VERSION 5.7 ;
  NOWIREEXTENSIONATPIN ON ;
  DIVIDERCHAR "/" ;
  BUSBITCHARS "[]" ;
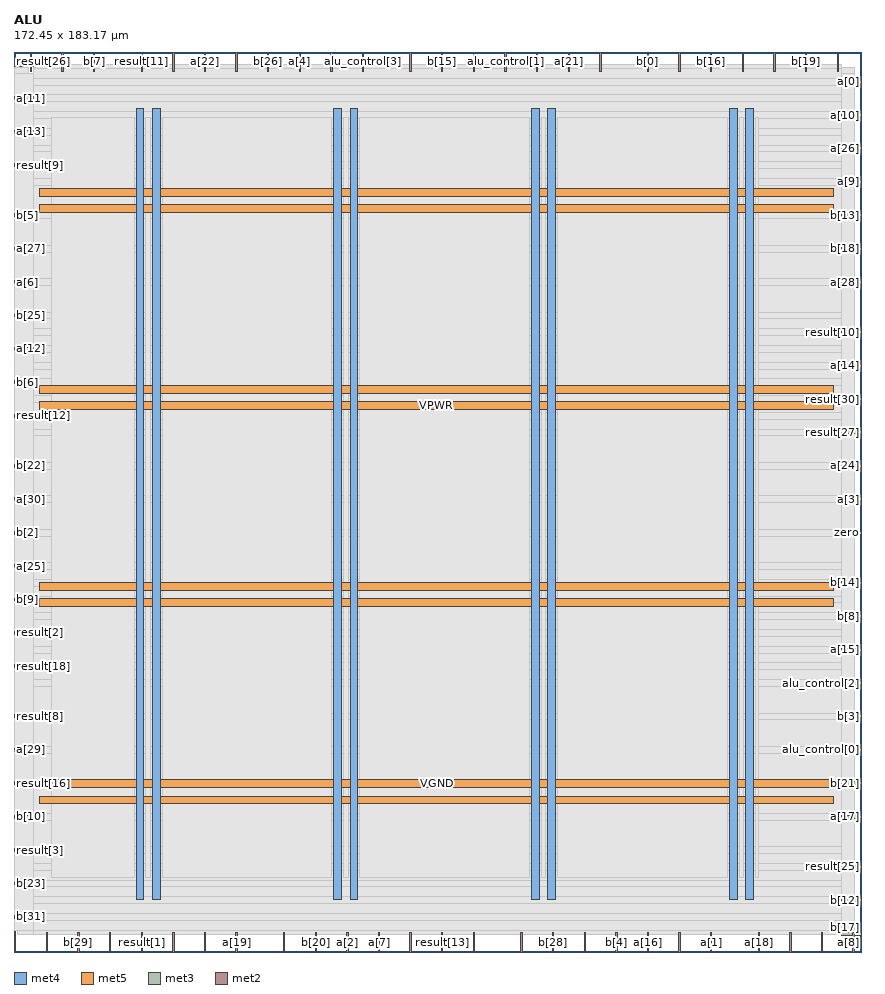
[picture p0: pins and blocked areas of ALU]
MACRO ALU
  CLASS BLOCK ;
  FOREIGN ALU ;
  ORIGIN 0.000 0.000 ;
  SIZE 172.450 BY 183.170 ;
  PIN VGND
    DIRECTION INOUT ;
    USE GROUND ;
    PORT
      LAYER met4 ;
        RECT 28.145 10.640 29.745 171.600 ;
    END
    PORT
      LAYER met4 ;
        RECT 68.395 10.640 69.995 171.600 ;
    END
    PORT
      LAYER met4 ;
        RECT 108.645 10.640 110.245 171.600 ;
    END
    PORT
      LAYER met4 ;
        RECT 148.895 10.640 150.495 171.600 ;
    END
    PORT
      LAYER met5 ;
        RECT 5.280 33.440 166.760 35.040 ;
    END
    PORT
      LAYER met5 ;
        RECT 5.280 73.560 166.760 75.160 ;
    END
    PORT
      LAYER met5 ;
        RECT 5.280 113.680 166.760 115.280 ;
    END
    PORT
      LAYER met5 ;
        RECT 5.280 153.800 166.760 155.400 ;
    END
  END VGND
  PIN VPWR
    DIRECTION INOUT ;
    USE POWER ;
    PORT
      LAYER met4 ;
        RECT 24.845 10.640 26.445 171.600 ;
    END
    PORT
      LAYER met4 ;
        RECT 65.095 10.640 66.695 171.600 ;
    END
    PORT
      LAYER met4 ;
        RECT 105.345 10.640 106.945 171.600 ;
    END
    PORT
      LAYER met4 ;
        RECT 145.595 10.640 147.195 171.600 ;
    END
    PORT
      LAYER met5 ;
        RECT 5.280 30.140 166.760 31.740 ;
    END
    PORT
      LAYER met5 ;
        RECT 5.280 70.260 166.760 71.860 ;
    END
    PORT
      LAYER met5 ;
        RECT 5.280 110.380 166.760 111.980 ;
    END
    PORT
      LAYER met5 ;
        RECT 5.280 150.500 166.760 152.100 ;
    END
  END VPWR
  PIN a[0]
    DIRECTION INPUT ;
    USE SIGNAL ;
    ANTENNAGATEAREA 0.213000 ;
    PORT
      LAYER met3 ;
        RECT 168.450 176.840 172.450 177.440 ;
    END
  END a[0]
  PIN a[10]
    DIRECTION INPUT ;
    USE SIGNAL ;
    ANTENNAGATEAREA 0.213000 ;
    PORT
      LAYER met3 ;
        RECT 168.450 170.040 172.450 170.640 ;
    END
  END a[10]
  PIN a[11]
    DIRECTION INPUT ;
    USE SIGNAL ;
    ANTENNAGATEAREA 0.159000 ;
    PORT
      LAYER met3 ;
        RECT 0.000 173.440 4.000 174.040 ;
    END
  END a[11]
  PIN a[12]
    DIRECTION INPUT ;
    USE SIGNAL ;
    ANTENNAGATEAREA 0.196500 ;
    PORT
      LAYER met3 ;
        RECT 0.000 122.440 4.000 123.040 ;
    END
  END a[12]
  PIN a[13]
    DIRECTION INPUT ;
    USE SIGNAL ;
    ANTENNAGATEAREA 0.213000 ;
    PORT
      LAYER met3 ;
        RECT 0.000 166.640 4.000 167.240 ;
    END
  END a[13]
  PIN a[14]
    DIRECTION INPUT ;
    USE SIGNAL ;
    ANTENNAGATEAREA 0.196500 ;
    PORT
      LAYER met3 ;
        RECT 168.450 119.040 172.450 119.640 ;
    END
  END a[14]
  PIN a[15]
    DIRECTION INPUT ;
    USE SIGNAL ;
    ANTENNAGATEAREA 0.213000 ;
    PORT
      LAYER met3 ;
        RECT 168.450 61.240 172.450 61.840 ;
    END
  END a[15]
  PIN a[16]
    DIRECTION INPUT ;
    USE SIGNAL ;
    ANTENNAGATEAREA 0.213000 ;
    PORT
      LAYER met2 ;
        RECT 128.890 0.000 129.170 4.000 ;
    END
  END a[16]
  PIN a[17]
    DIRECTION INPUT ;
    USE SIGNAL ;
    ANTENNAGATEAREA 0.196500 ;
    PORT
      LAYER met3 ;
        RECT 168.450 27.240 172.450 27.840 ;
    END
  END a[17]
  PIN a[18]
    DIRECTION INPUT ;
    USE SIGNAL ;
    ANTENNAGATEAREA 0.196500 ;
    PORT
      LAYER met2 ;
        RECT 151.430 0.000 151.710 4.000 ;
    END
  END a[18]
  PIN a[19]
    DIRECTION INPUT ;
    USE SIGNAL ;
    ANTENNAGATEAREA 0.213000 ;
    PORT
      LAYER met2 ;
        RECT 45.170 0.000 45.450 4.000 ;
    END
  END a[19]
  PIN a[1]
    DIRECTION INPUT ;
    USE SIGNAL ;
    ANTENNAGATEAREA 0.213000 ;
    PORT
      LAYER met2 ;
        RECT 141.770 0.000 142.050 4.000 ;
    END
  END a[1]
  PIN a[20]
    DIRECTION INPUT ;
    USE SIGNAL ;
    ANTENNAGATEAREA 0.213000 ;
    PORT
      LAYER met2 ;
        RECT 19.410 0.000 19.690 4.000 ;
    END
  END a[20]
  PIN a[21]
    DIRECTION INPUT ;
    USE SIGNAL ;
    ANTENNAGATEAREA 0.196500 ;
    PORT
      LAYER met2 ;
        RECT 112.790 179.170 113.070 183.170 ;
    END
  END a[21]
  PIN a[22]
    DIRECTION INPUT ;
    USE SIGNAL ;
    ANTENNAGATEAREA 0.213000 ;
    PORT
      LAYER met2 ;
        RECT 38.730 179.170 39.010 183.170 ;
    END
  END a[22]
  PIN a[23]
    DIRECTION INPUT ;
    USE SIGNAL ;
    ANTENNAGATEAREA 0.213000 ;
    PORT
      LAYER met2 ;
        RECT 45.170 179.170 45.450 183.170 ;
    END
  END a[23]
  PIN a[24]
    DIRECTION INPUT ;
    USE SIGNAL ;
    ANTENNAGATEAREA 0.159000 ;
    PORT
      LAYER met3 ;
        RECT 168.450 98.640 172.450 99.240 ;
    END
  END a[24]
  PIN a[25]
    DIRECTION INPUT ;
    USE SIGNAL ;
    ANTENNAGATEAREA 0.213000 ;
    PORT
      LAYER met3 ;
        RECT 0.000 78.240 4.000 78.840 ;
    END
  END a[25]
  PIN a[26]
    DIRECTION INPUT ;
    USE SIGNAL ;
    ANTENNAGATEAREA 0.159000 ;
    PORT
      LAYER met3 ;
        RECT 168.450 163.240 172.450 163.840 ;
    END
  END a[26]
  PIN a[27]
    DIRECTION INPUT ;
    USE SIGNAL ;
    ANTENNAGATEAREA 0.213000 ;
    PORT
      LAYER met3 ;
        RECT 0.000 142.840 4.000 143.440 ;
    END
  END a[27]
  PIN a[28]
    DIRECTION INPUT ;
    USE SIGNAL ;
    ANTENNAGATEAREA 0.159000 ;
    PORT
      LAYER met3 ;
        RECT 168.450 136.040 172.450 136.640 ;
    END
  END a[28]
  PIN a[29]
    DIRECTION INPUT ;
    USE SIGNAL ;
    ANTENNAGATEAREA 0.213000 ;
    PORT
      LAYER met3 ;
        RECT 0.000 40.840 4.000 41.440 ;
    END
  END a[29]
  PIN a[2]
    DIRECTION INPUT ;
    USE SIGNAL ;
    ANTENNAGATEAREA 0.213000 ;
    PORT
      LAYER met2 ;
        RECT 67.710 0.000 67.990 4.000 ;
    END
  END a[2]
  PIN a[30]
    DIRECTION INPUT ;
    USE SIGNAL ;
    ANTENNAGATEAREA 0.213000 ;
    PORT
      LAYER met3 ;
        RECT 0.000 91.840 4.000 92.440 ;
    END
  END a[30]
  PIN a[31]
    DIRECTION INPUT ;
    USE SIGNAL ;
    ANTENNAGATEAREA 0.213000 ;
    PORT
      LAYER met2 ;
        RECT 106.350 179.170 106.630 183.170 ;
    END
  END a[31]
  PIN a[3]
    DIRECTION INPUT ;
    USE SIGNAL ;
    ANTENNAGATEAREA 0.126000 ;
    PORT
      LAYER met3 ;
        RECT 168.450 91.840 172.450 92.440 ;
    END
  END a[3]
  PIN a[4]
    DIRECTION INPUT ;
    USE SIGNAL ;
    ANTENNAGATEAREA 0.213000 ;
    PORT
      LAYER met2 ;
        RECT 58.050 179.170 58.330 183.170 ;
    END
  END a[4]
  PIN a[5]
    DIRECTION INPUT ;
    USE SIGNAL ;
    ANTENNAGATEAREA 0.213000 ;
    PORT
      LAYER met2 ;
        RECT 64.490 179.170 64.770 183.170 ;
    END
  END a[5]
  PIN a[6]
    DIRECTION INPUT ;
    USE SIGNAL ;
    ANTENNAGATEAREA 0.213000 ;
    PORT
      LAYER met3 ;
        RECT 0.000 136.040 4.000 136.640 ;
    END
  END a[6]
  PIN a[7]
    DIRECTION INPUT ;
    USE SIGNAL ;
    ANTENNAGATEAREA 0.126000 ;
    PORT
      LAYER met2 ;
        RECT 74.150 0.000 74.430 4.000 ;
    END
  END a[7]
  PIN a[8]
    DIRECTION INPUT ;
    USE SIGNAL ;
    ANTENNAGATEAREA 0.213000 ;
    PORT
      LAYER met2 ;
        RECT 170.750 0.000 171.030 4.000 ;
    END
  END a[8]
  PIN a[9]
    DIRECTION INPUT ;
    USE SIGNAL ;
    ANTENNAGATEAREA 0.159000 ;
    PORT
      LAYER met3 ;
        RECT 168.450 156.440 172.450 157.040 ;
    END
  END a[9]
  PIN alu_control[0]
    DIRECTION INPUT ;
    USE SIGNAL ;
    ANTENNAGATEAREA 0.159000 ;
    PORT
      LAYER met3 ;
        RECT 168.450 40.840 172.450 41.440 ;
    END
  END alu_control[0]
  PIN alu_control[1]
    DIRECTION INPUT ;
    USE SIGNAL ;
    ANTENNAGATEAREA 0.159000 ;
    PORT
      LAYER met2 ;
        RECT 99.910 179.170 100.190 183.170 ;
    END
  END alu_control[1]
  PIN alu_control[2]
    DIRECTION INPUT ;
    USE SIGNAL ;
    ANTENNAGATEAREA 0.213000 ;
    PORT
      LAYER met3 ;
        RECT 168.450 54.440 172.450 55.040 ;
    END
  END alu_control[2]
  PIN alu_control[3]
    DIRECTION INPUT ;
    USE SIGNAL ;
    ANTENNAGATEAREA 0.159000 ;
    PORT
      LAYER met2 ;
        RECT 70.930 179.170 71.210 183.170 ;
    END
  END alu_control[3]
  PIN b[0]
    DIRECTION INPUT ;
    USE SIGNAL ;
    ANTENNAGATEAREA 0.213000 ;
    PORT
      LAYER met2 ;
        RECT 128.890 179.170 129.170 183.170 ;
    END
  END b[0]
  PIN b[10]
    DIRECTION INPUT ;
    USE SIGNAL ;
    ANTENNAGATEAREA 0.213000 ;
    PORT
      LAYER met3 ;
        RECT 0.000 27.240 4.000 27.840 ;
    END
  END b[10]
  PIN b[11]
    DIRECTION INPUT ;
    USE SIGNAL ;
    ANTENNAGATEAREA 0.213000 ;
    PORT
      LAYER met2 ;
        RECT 38.730 0.000 39.010 4.000 ;
    END
  END b[11]
  PIN b[12]
    DIRECTION INPUT ;
    USE SIGNAL ;
    ANTENNAGATEAREA 0.159000 ;
    PORT
      LAYER met3 ;
        RECT 168.450 10.240 172.450 10.840 ;
    END
  END b[12]
  PIN b[13]
    DIRECTION INPUT ;
    USE SIGNAL ;
    ANTENNAGATEAREA 0.159000 ;
    PORT
      LAYER met3 ;
        RECT 168.450 149.640 172.450 150.240 ;
    END
  END b[13]
  PIN b[14]
    DIRECTION INPUT ;
    USE SIGNAL ;
    ANTENNAGATEAREA 0.213000 ;
    PORT
      LAYER met3 ;
        RECT 168.450 74.840 172.450 75.440 ;
    END
  END b[14]
  PIN b[15]
    DIRECTION INPUT ;
    USE SIGNAL ;
    ANTENNAGATEAREA 0.159000 ;
    PORT
      LAYER met2 ;
        RECT 87.030 179.170 87.310 183.170 ;
    END
  END b[15]
  PIN b[16]
    DIRECTION INPUT ;
    USE SIGNAL ;
    ANTENNAGATEAREA 0.213000 ;
    PORT
      LAYER met2 ;
        RECT 141.770 179.170 142.050 183.170 ;
    END
  END b[16]
  PIN b[17]
    DIRECTION INPUT ;
    USE SIGNAL ;
    ANTENNAGATEAREA 0.213000 ;
    PORT
      LAYER met3 ;
        RECT 168.450 3.440 172.450 4.040 ;
    END
  END b[17]
  PIN b[18]
    DIRECTION INPUT ;
    USE SIGNAL ;
    ANTENNAGATEAREA 0.159000 ;
    PORT
      LAYER met3 ;
        RECT 168.450 142.840 172.450 143.440 ;
    END
  END b[18]
  PIN b[19]
    DIRECTION INPUT ;
    USE SIGNAL ;
    ANTENNAGATEAREA 0.159000 ;
    PORT
      LAYER met2 ;
        RECT 161.090 179.170 161.370 183.170 ;
    END
  END b[19]
  PIN b[1]
    DIRECTION INPUT ;
    USE SIGNAL ;
    ANTENNAGATEAREA 0.196500 ;
    PORT
      LAYER met2 ;
        RECT 93.470 179.170 93.750 183.170 ;
    END
  END b[1]
  PIN b[20]
    DIRECTION INPUT ;
    USE SIGNAL ;
    ANTENNAGATEAREA 0.159000 ;
    PORT
      LAYER met2 ;
        RECT 61.270 0.000 61.550 4.000 ;
    END
  END b[20]
  PIN b[21]
    DIRECTION INPUT ;
    USE SIGNAL ;
    ANTENNAGATEAREA 0.126000 ;
    PORT
      LAYER met3 ;
        RECT 168.450 34.040 172.450 34.640 ;
    END
  END b[21]
  PIN b[22]
    DIRECTION INPUT ;
    USE SIGNAL ;
    ANTENNAGATEAREA 0.159000 ;
    PORT
      LAYER met3 ;
        RECT 0.000 98.640 4.000 99.240 ;
    END
  END b[22]
  PIN b[23]
    DIRECTION INPUT ;
    USE SIGNAL ;
    ANTENNAGATEAREA 0.159000 ;
    PORT
      LAYER met3 ;
        RECT 0.000 13.640 4.000 14.240 ;
    END
  END b[23]
  PIN b[24]
    DIRECTION INPUT ;
    USE SIGNAL ;
    ANTENNAGATEAREA 0.159000 ;
    PORT
      LAYER met2 ;
        RECT 164.310 0.000 164.590 4.000 ;
    END
  END b[24]
  PIN b[25]
    DIRECTION INPUT ;
    USE SIGNAL ;
    ANTENNAGATEAREA 0.159000 ;
    PORT
      LAYER met3 ;
        RECT 0.000 129.240 4.000 129.840 ;
    END
  END b[25]
  PIN b[26]
    DIRECTION INPUT ;
    USE SIGNAL ;
    ANTENNAGATEAREA 0.213000 ;
    PORT
      LAYER met2 ;
        RECT 51.610 179.170 51.890 183.170 ;
    END
  END b[26]
  PIN b[27]
    DIRECTION INPUT ;
    USE SIGNAL ;
    ANTENNAGATEAREA 0.213000 ;
    PORT
      LAYER met2 ;
        RECT 148.210 179.170 148.490 183.170 ;
    END
  END b[27]
  PIN b[28]
    DIRECTION INPUT ;
    USE SIGNAL ;
    ANTENNAGATEAREA 0.159000 ;
    PORT
      LAYER met2 ;
        RECT 109.570 0.000 109.850 4.000 ;
    END
  END b[28]
  PIN b[29]
    DIRECTION INPUT ;
    USE SIGNAL ;
    ANTENNAGATEAREA 0.159000 ;
    PORT
      LAYER met2 ;
        RECT 12.970 0.000 13.250 4.000 ;
    END
  END b[29]
  PIN b[2]
    DIRECTION INPUT ;
    USE SIGNAL ;
    ANTENNAGATEAREA 0.196500 ;
    PORT
      LAYER met3 ;
        RECT 0.000 85.040 4.000 85.640 ;
    END
  END b[2]
  PIN b[30]
    DIRECTION INPUT ;
    USE SIGNAL ;
    ANTENNAGATEAREA 0.213000 ;
    PORT
      LAYER met2 ;
        RECT 157.870 0.000 158.150 4.000 ;
    END
  END b[30]
  PIN b[31]
    DIRECTION INPUT ;
    USE SIGNAL ;
    ANTENNAGATEAREA 0.213000 ;
    PORT
      LAYER met3 ;
        RECT 0.000 6.840 4.000 7.440 ;
    END
  END b[31]
  PIN b[3]
    DIRECTION INPUT ;
    USE SIGNAL ;
    ANTENNAGATEAREA 0.159000 ;
    PORT
      LAYER met3 ;
        RECT 168.450 47.640 172.450 48.240 ;
    END
  END b[3]
  PIN b[4]
    DIRECTION INPUT ;
    USE SIGNAL ;
    ANTENNAGATEAREA 0.213000 ;
    PORT
      LAYER met2 ;
        RECT 122.450 0.000 122.730 4.000 ;
    END
  END b[4]
  PIN b[5]
    DIRECTION INPUT ;
    USE SIGNAL ;
    ANTENNAGATEAREA 0.213000 ;
    PORT
      LAYER met3 ;
        RECT 0.000 149.640 4.000 150.240 ;
    END
  END b[5]
  PIN b[6]
    DIRECTION INPUT ;
    USE SIGNAL ;
    ANTENNAGATEAREA 0.213000 ;
    PORT
      LAYER met3 ;
        RECT 0.000 115.640 4.000 116.240 ;
    END
  END b[6]
  PIN b[7]
    DIRECTION INPUT ;
    USE SIGNAL ;
    ANTENNAGATEAREA 0.213000 ;
    PORT
      LAYER met2 ;
        RECT 16.190 179.170 16.470 183.170 ;
    END
  END b[7]
  PIN b[8]
    DIRECTION INPUT ;
    USE SIGNAL ;
    ANTENNAGATEAREA 0.159000 ;
    PORT
      LAYER met3 ;
        RECT 168.450 68.040 172.450 68.640 ;
    END
  END b[8]
  PIN b[9]
    DIRECTION INPUT ;
    USE SIGNAL ;
    ANTENNAGATEAREA 0.213000 ;
    PORT
      LAYER met3 ;
        RECT 0.000 71.440 4.000 72.040 ;
    END
  END b[9]
  PIN result[0]
    DIRECTION OUTPUT TRISTATE ;
    USE SIGNAL ;
    ANTENNADIFFAREA 0.795200 ;
    PORT
      LAYER met2 ;
        RECT 135.330 0.000 135.610 4.000 ;
    END
  END result[0]
  PIN result[10]
    DIRECTION OUTPUT TRISTATE ;
    USE SIGNAL ;
    ANTENNADIFFAREA 0.795200 ;
    PORT
      LAYER met3 ;
        RECT 168.450 125.840 172.450 126.440 ;
    END
  END result[10]
  PIN result[11]
    DIRECTION OUTPUT TRISTATE ;
    USE SIGNAL ;
    ANTENNADIFFAREA 0.795200 ;
    PORT
      LAYER met2 ;
        RECT 25.850 179.170 26.130 183.170 ;
    END
  END result[11]
  PIN result[12]
    DIRECTION OUTPUT TRISTATE ;
    USE SIGNAL ;
    ANTENNADIFFAREA 0.795200 ;
    PORT
      LAYER met3 ;
        RECT 0.000 108.840 4.000 109.440 ;
    END
  END result[12]
  PIN result[13]
    DIRECTION OUTPUT TRISTATE ;
    USE SIGNAL ;
    ANTENNADIFFAREA 0.795200 ;
    PORT
      LAYER met2 ;
        RECT 87.030 0.000 87.310 4.000 ;
    END
  END result[13]
  PIN result[14]
    DIRECTION OUTPUT TRISTATE ;
    USE SIGNAL ;
    ANTENNADIFFAREA 0.795200 ;
    PORT
      LAYER met2 ;
        RECT 0.090 0.000 0.370 4.000 ;
    END
  END result[14]
  PIN result[15]
    DIRECTION OUTPUT TRISTATE ;
    USE SIGNAL ;
    ANTENNADIFFAREA 0.795200 ;
    PORT
      LAYER met2 ;
        RECT 103.130 0.000 103.410 4.000 ;
    END
  END result[15]
  PIN result[16]
    DIRECTION OUTPUT TRISTATE ;
    USE SIGNAL ;
    ANTENNADIFFAREA 0.795200 ;
    PORT
      LAYER met3 ;
        RECT 0.000 34.040 4.000 34.640 ;
    END
  END result[16]
  PIN result[17]
    DIRECTION OUTPUT TRISTATE ;
    USE SIGNAL ;
    ANTENNADIFFAREA 0.795200 ;
    PORT
      LAYER met2 ;
        RECT 80.590 179.170 80.870 183.170 ;
    END
  END result[17]
  PIN result[18]
    DIRECTION OUTPUT TRISTATE ;
    USE SIGNAL ;
    ANTENNADIFFAREA 0.795200 ;
    PORT
      LAYER met3 ;
        RECT 0.000 57.840 4.000 58.440 ;
    END
  END result[18]
  PIN result[19]
    DIRECTION OUTPUT TRISTATE ;
    USE SIGNAL ;
    ANTENNADIFFAREA 0.795200 ;
    PORT
      LAYER met3 ;
        RECT 0.000 180.240 4.000 180.840 ;
    END
  END result[19]
  PIN result[1]
    DIRECTION OUTPUT TRISTATE ;
    USE SIGNAL ;
    ANTENNADIFFAREA 0.795200 ;
    PORT
      LAYER met2 ;
        RECT 25.850 0.000 26.130 4.000 ;
    END
  END result[1]
  PIN result[20]
    DIRECTION OUTPUT TRISTATE ;
    USE SIGNAL ;
    ANTENNADIFFAREA 0.795200 ;
    PORT
      LAYER met2 ;
        RECT 6.530 0.000 6.810 4.000 ;
    END
  END result[20]
  PIN result[21]
    DIRECTION OUTPUT TRISTATE ;
    USE SIGNAL ;
    ANTENNADIFFAREA 0.795200 ;
    PORT
      LAYER met2 ;
        RECT 154.650 179.170 154.930 183.170 ;
    END
  END result[21]
  PIN result[22]
    DIRECTION OUTPUT TRISTATE ;
    USE SIGNAL ;
    ANTENNADIFFAREA 0.795200 ;
    PORT
      LAYER met2 ;
        RECT 119.230 179.170 119.510 183.170 ;
    END
  END result[22]
  PIN result[23]
    DIRECTION OUTPUT TRISTATE ;
    USE SIGNAL ;
    ANTENNADIFFAREA 0.795200 ;
    PORT
      LAYER met2 ;
        RECT 80.590 0.000 80.870 4.000 ;
    END
  END result[23]
  PIN result[24]
    DIRECTION OUTPUT TRISTATE ;
    USE SIGNAL ;
    ANTENNADIFFAREA 0.795200 ;
    PORT
      LAYER met2 ;
        RECT 167.530 179.170 167.810 183.170 ;
    END
  END result[24]
  PIN result[25]
    DIRECTION OUTPUT TRISTATE ;
    USE SIGNAL ;
    ANTENNADIFFAREA 0.445500 ;
    PORT
      LAYER met3 ;
        RECT 168.450 17.040 172.450 17.640 ;
    END
  END result[25]
  PIN result[26]
    DIRECTION OUTPUT TRISTATE ;
    USE SIGNAL ;
    ANTENNADIFFAREA 0.795200 ;
    PORT
      LAYER met2 ;
        RECT 3.310 179.170 3.590 183.170 ;
    END
  END result[26]
  PIN result[27]
    DIRECTION OUTPUT TRISTATE ;
    USE SIGNAL ;
    ANTENNADIFFAREA 0.445500 ;
    PORT
      LAYER met3 ;
        RECT 168.450 105.440 172.450 106.040 ;
    END
  END result[27]
  PIN result[28]
    DIRECTION OUTPUT TRISTATE ;
    USE SIGNAL ;
    ANTENNADIFFAREA 0.795200 ;
    PORT
      LAYER met2 ;
        RECT 32.290 0.000 32.570 4.000 ;
    END
  END result[28]
  PIN result[29]
    DIRECTION OUTPUT TRISTATE ;
    USE SIGNAL ;
    ANTENNADIFFAREA 0.795200 ;
    PORT
      LAYER met2 ;
        RECT 54.830 0.000 55.110 4.000 ;
    END
  END result[29]
  PIN result[2]
    DIRECTION OUTPUT TRISTATE ;
    USE SIGNAL ;
    ANTENNADIFFAREA 0.795200 ;
    PORT
      LAYER met3 ;
        RECT 0.000 64.640 4.000 65.240 ;
    END
  END result[2]
  PIN result[30]
    DIRECTION OUTPUT TRISTATE ;
    USE SIGNAL ;
    ANTENNADIFFAREA 0.795200 ;
    PORT
      LAYER met3 ;
        RECT 168.450 112.240 172.450 112.840 ;
    END
  END result[30]
  PIN result[31]
    DIRECTION OUTPUT TRISTATE ;
    USE SIGNAL ;
    ANTENNADIFFAREA 0.795200 ;
    PORT
      LAYER met2 ;
        RECT 93.470 0.000 93.750 4.000 ;
    END
  END result[31]
  PIN result[3]
    DIRECTION OUTPUT TRISTATE ;
    USE SIGNAL ;
    ANTENNADIFFAREA 0.795200 ;
    PORT
      LAYER met3 ;
        RECT 0.000 20.440 4.000 21.040 ;
    END
  END result[3]
  PIN result[4]
    DIRECTION OUTPUT TRISTATE ;
    USE SIGNAL ;
    ANTENNADIFFAREA 0.795200 ;
    PORT
      LAYER met2 ;
        RECT 135.330 179.170 135.610 183.170 ;
    END
  END result[4]
  PIN result[5]
    DIRECTION OUTPUT TRISTATE ;
    USE SIGNAL ;
    ANTENNADIFFAREA 0.445500 ;
    PORT
      LAYER met2 ;
        RECT 9.750 179.170 10.030 183.170 ;
    END
  END result[5]
  PIN result[6]
    DIRECTION OUTPUT TRISTATE ;
    USE SIGNAL ;
    ANTENNADIFFAREA 0.795200 ;
    PORT
      LAYER met2 ;
        RECT 32.290 179.170 32.570 183.170 ;
    END
  END result[6]
  PIN result[7]
    DIRECTION OUTPUT TRISTATE ;
    USE SIGNAL ;
    ANTENNADIFFAREA 0.795200 ;
    PORT
      LAYER met2 ;
        RECT 116.010 0.000 116.290 4.000 ;
    END
  END result[7]
  PIN result[8]
    DIRECTION OUTPUT TRISTATE ;
    USE SIGNAL ;
    ANTENNADIFFAREA 0.795200 ;
    PORT
      LAYER met3 ;
        RECT 0.000 47.640 4.000 48.240 ;
    END
  END result[8]
  PIN result[9]
    DIRECTION OUTPUT TRISTATE ;
    USE SIGNAL ;
    ANTENNADIFFAREA 0.795200 ;
    PORT
      LAYER met3 ;
        RECT 0.000 159.840 4.000 160.440 ;
    END
  END result[9]
  PIN zero
    DIRECTION OUTPUT TRISTATE ;
    USE SIGNAL ;
    ANTENNADIFFAREA 0.445500 ;
    PORT
      LAYER met3 ;
        RECT 168.450 85.040 172.450 85.640 ;
    END
  END zero
  OBS
      LAYER li1 ;
        RECT 5.520 10.795 166.520 171.445 ;
      LAYER met1 ;
        RECT 0.070 8.200 171.050 172.340 ;
      LAYER met2 ;
        RECT 0.100 178.890 3.030 180.045 ;
        RECT 3.870 178.890 9.470 180.045 ;
        RECT 10.310 178.890 15.910 180.045 ;
        RECT 16.750 178.890 25.570 180.045 ;
        RECT 26.410 178.890 32.010 180.045 ;
        RECT 32.850 178.890 38.450 180.045 ;
        RECT 39.290 178.890 44.890 180.045 ;
        RECT 45.730 178.890 51.330 180.045 ;
        RECT 52.170 178.890 57.770 180.045 ;
        RECT 58.610 178.890 64.210 180.045 ;
        RECT 65.050 178.890 70.650 180.045 ;
        RECT 71.490 178.890 80.310 180.045 ;
        RECT 81.150 178.890 86.750 180.045 ;
        RECT 87.590 178.890 93.190 180.045 ;
        RECT 94.030 178.890 99.630 180.045 ;
        RECT 100.470 178.890 106.070 180.045 ;
        RECT 106.910 178.890 112.510 180.045 ;
        RECT 113.350 178.890 118.950 180.045 ;
        RECT 119.790 178.890 128.610 180.045 ;
        RECT 129.450 178.890 135.050 180.045 ;
        RECT 135.890 178.890 141.490 180.045 ;
        RECT 142.330 178.890 147.930 180.045 ;
        RECT 148.770 178.890 154.370 180.045 ;
        RECT 155.210 178.890 160.810 180.045 ;
        RECT 161.650 178.890 167.250 180.045 ;
        RECT 168.090 178.890 171.020 180.045 ;
        RECT 0.100 4.280 171.020 178.890 ;
        RECT 0.650 3.555 6.250 4.280 ;
        RECT 7.090 3.555 12.690 4.280 ;
        RECT 13.530 3.555 19.130 4.280 ;
        RECT 19.970 3.555 25.570 4.280 ;
        RECT 26.410 3.555 32.010 4.280 ;
        RECT 32.850 3.555 38.450 4.280 ;
        RECT 39.290 3.555 44.890 4.280 ;
        RECT 45.730 3.555 54.550 4.280 ;
        RECT 55.390 3.555 60.990 4.280 ;
        RECT 61.830 3.555 67.430 4.280 ;
        RECT 68.270 3.555 73.870 4.280 ;
        RECT 74.710 3.555 80.310 4.280 ;
        RECT 81.150 3.555 86.750 4.280 ;
        RECT 87.590 3.555 93.190 4.280 ;
        RECT 94.030 3.555 102.850 4.280 ;
        RECT 103.690 3.555 109.290 4.280 ;
        RECT 110.130 3.555 115.730 4.280 ;
        RECT 116.570 3.555 122.170 4.280 ;
        RECT 123.010 3.555 128.610 4.280 ;
        RECT 129.450 3.555 135.050 4.280 ;
        RECT 135.890 3.555 141.490 4.280 ;
        RECT 142.330 3.555 151.150 4.280 ;
        RECT 151.990 3.555 157.590 4.280 ;
        RECT 158.430 3.555 164.030 4.280 ;
        RECT 164.870 3.555 170.470 4.280 ;
      LAYER met3 ;
        RECT 4.400 179.840 168.450 180.690 ;
        RECT 3.990 177.840 168.450 179.840 ;
        RECT 3.990 176.440 168.050 177.840 ;
        RECT 3.990 174.440 168.450 176.440 ;
        RECT 4.400 173.040 168.450 174.440 ;
        RECT 3.990 171.040 168.450 173.040 ;
        RECT 3.990 169.640 168.050 171.040 ;
        RECT 3.990 167.640 168.450 169.640 ;
        RECT 4.400 166.240 168.450 167.640 ;
        RECT 3.990 164.240 168.450 166.240 ;
        RECT 3.990 162.840 168.050 164.240 ;
        RECT 3.990 160.840 168.450 162.840 ;
        RECT 4.400 159.440 168.450 160.840 ;
        RECT 3.990 157.440 168.450 159.440 ;
        RECT 3.990 156.040 168.050 157.440 ;
        RECT 3.990 150.640 168.450 156.040 ;
        RECT 4.400 149.240 168.050 150.640 ;
        RECT 3.990 143.840 168.450 149.240 ;
        RECT 4.400 142.440 168.050 143.840 ;
        RECT 3.990 137.040 168.450 142.440 ;
        RECT 4.400 135.640 168.050 137.040 ;
        RECT 3.990 130.240 168.450 135.640 ;
        RECT 4.400 128.840 168.450 130.240 ;
        RECT 3.990 126.840 168.450 128.840 ;
        RECT 3.990 125.440 168.050 126.840 ;
        RECT 3.990 123.440 168.450 125.440 ;
        RECT 4.400 122.040 168.450 123.440 ;
        RECT 3.990 120.040 168.450 122.040 ;
        RECT 3.990 118.640 168.050 120.040 ;
        RECT 3.990 116.640 168.450 118.640 ;
        RECT 4.400 115.240 168.450 116.640 ;
        RECT 3.990 113.240 168.450 115.240 ;
        RECT 3.990 111.840 168.050 113.240 ;
        RECT 3.990 109.840 168.450 111.840 ;
        RECT 4.400 108.440 168.450 109.840 ;
        RECT 3.990 106.440 168.450 108.440 ;
        RECT 3.990 105.040 168.050 106.440 ;
        RECT 3.990 99.640 168.450 105.040 ;
        RECT 4.400 98.240 168.050 99.640 ;
        RECT 3.990 92.840 168.450 98.240 ;
        RECT 4.400 91.440 168.050 92.840 ;
        RECT 3.990 86.040 168.450 91.440 ;
        RECT 4.400 84.640 168.050 86.040 ;
        RECT 3.990 79.240 168.450 84.640 ;
        RECT 4.400 77.840 168.450 79.240 ;
        RECT 3.990 75.840 168.450 77.840 ;
        RECT 3.990 74.440 168.050 75.840 ;
        RECT 3.990 72.440 168.450 74.440 ;
        RECT 4.400 71.040 168.450 72.440 ;
        RECT 3.990 69.040 168.450 71.040 ;
        RECT 3.990 67.640 168.050 69.040 ;
        RECT 3.990 65.640 168.450 67.640 ;
        RECT 4.400 64.240 168.450 65.640 ;
        RECT 3.990 62.240 168.450 64.240 ;
        RECT 3.990 60.840 168.050 62.240 ;
        RECT 3.990 58.840 168.450 60.840 ;
        RECT 4.400 57.440 168.450 58.840 ;
        RECT 3.990 55.440 168.450 57.440 ;
        RECT 3.990 54.040 168.050 55.440 ;
        RECT 3.990 48.640 168.450 54.040 ;
        RECT 4.400 47.240 168.050 48.640 ;
        RECT 3.990 41.840 168.450 47.240 ;
        RECT 4.400 40.440 168.050 41.840 ;
        RECT 3.990 35.040 168.450 40.440 ;
        RECT 4.400 33.640 168.050 35.040 ;
        RECT 3.990 28.240 168.450 33.640 ;
        RECT 4.400 26.840 168.050 28.240 ;
        RECT 3.990 21.440 168.450 26.840 ;
        RECT 4.400 20.040 168.450 21.440 ;
        RECT 3.990 18.040 168.450 20.040 ;
        RECT 3.990 16.640 168.050 18.040 ;
        RECT 3.990 14.640 168.450 16.640 ;
        RECT 4.400 13.240 168.450 14.640 ;
        RECT 3.990 11.240 168.450 13.240 ;
        RECT 3.990 9.840 168.050 11.240 ;
        RECT 3.990 7.840 168.450 9.840 ;
        RECT 4.400 6.440 168.450 7.840 ;
        RECT 3.990 4.440 168.450 6.440 ;
        RECT 3.990 3.575 168.050 4.440 ;
      LAYER met4 ;
        RECT 7.655 15.135 24.445 169.825 ;
        RECT 26.845 15.135 27.745 169.825 ;
        RECT 30.145 15.135 64.695 169.825 ;
        RECT 67.095 15.135 67.995 169.825 ;
        RECT 70.395 15.135 104.945 169.825 ;
        RECT 107.345 15.135 108.245 169.825 ;
        RECT 110.645 15.135 145.195 169.825 ;
        RECT 147.595 15.135 148.495 169.825 ;
        RECT 150.895 15.135 151.505 169.825 ;
  END
END ALU
END LIBRARY

